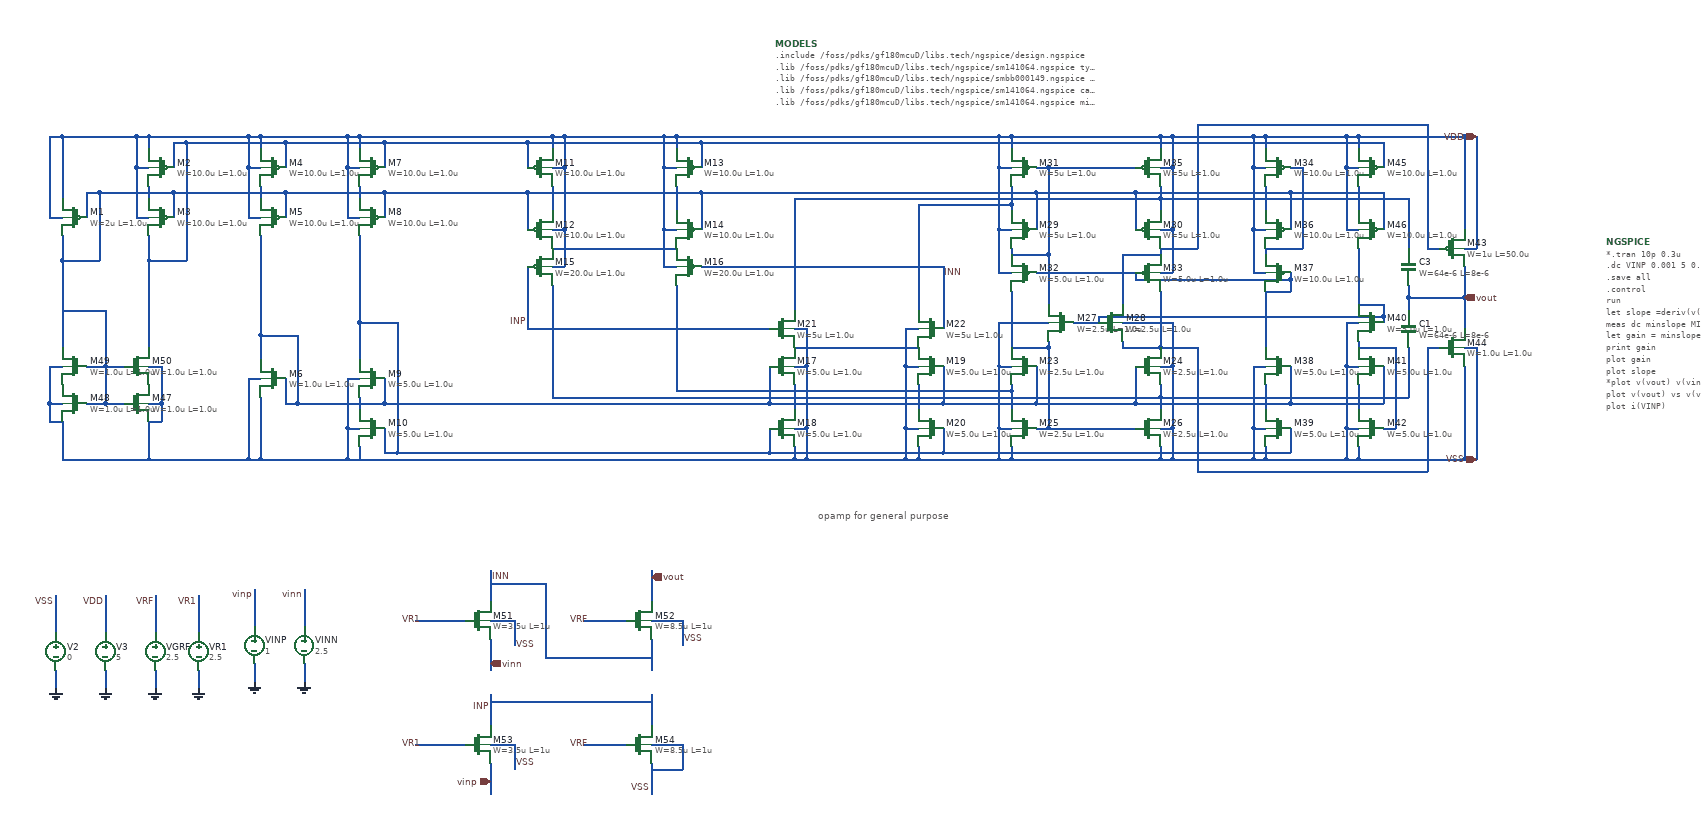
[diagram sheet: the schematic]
v {xschem version=3.4.8RC file_version=1.3}
G {}
K {}
V {}
S {}
F {}
E {}
P 4 1 -1130 460 {}
T {opamp for general purpose} -480 690 2 0 0.4 0.4 {}
N -910 300 -890 300 {
lab=VDD}
N -730 300 -710 300 {
lab=VDD}
N -910 90 -910 110 {
lab=VDD}
N -910 140 -890 140 {
lab=VDD}
N -950 100 -950 140 {
lab=#net1}
N -190 560 -190 610 {
lab=VSS}
N -190 560 -170 560 {
lab=VSS}
N -170 590 -170 610 {
lab=VSS}
N -170 90 -170 110 {
lab=VDD}
N -190 140 -170 140 {
lab=VDD}
N 70 90 70 110 {
lab=VDD}
N 70 140 90 140 {
lab=VDD}
N 90 140 90 240 {
lab=VDD}
N 70 560 90 560 {
lab=VSS}
N 70 590 70 610 {
lab=VSS}
N -950 300 -950 400 {
lab=INP}
N -340 400 -320 400 {
lab=VSS}
N -520 460 -500 460 {
lab=VSS}
N -500 560 -500 610 {
lab=VSS}
N -520 560 -500 560 {
lab=VSS}
N -520 490 -520 530 {
lab=#net2}
N -520 590 -520 610 {
lab=VSS}
N -560 560 -560 600 {
lab=#net3}
N -560 460 -560 520 {
lab=#net4}
N -910 240 -890 240 {
lab=VDD}
N -910 170 -910 210 {
lab=#net5}
N -950 180 -950 240 {
lab=#net6}
N -190 140 -190 240 {
lab=VDD}
N -190 240 -170 240 {
lab=VDD}
N -170 200 -170 210 {
lab=#net7}
N -190 460 -170 460 {
lab=VSS}
N -190 460 -190 560 {
lab=VSS}
N -170 500 -170 530 {
lab=#net8}
N 70 510 70 530 {
lab=#net9}
N 70 460 90 460 {
lab=VSS}
N -670 300 -280 300 {
lab=INN}
N -280 300 -280 400 {
lab=INN}
N 70 240 90 240 {
lab=VDD}
N 70 190 70 210 {
lab=#net10}
N -910 270 -710 270 {
lab=#net11}
N -950 400 -560 400 {
lab=INP}
N -520 430 -320 430 {
lab=#net12}
N -170 270 -170 280 {
lab=#net13}
N -190 310 -170 310 {
lab=VDD}
N -190 240 -190 310 {
lab=VDD}
N -110 560 30 560 {
lab=#net14}
N 90 560 90 610 {
lab=VSS}
N -70 390 -30 390 {
lab=#net15}
N 70 310 90 310 {
lab=VDD}
N 90 240 90 310 {
lab=VDD}
N 70 270 70 280 {
lab=#net16}
N 10 390 90 390 {
lab=VSS}
N 90 390 90 460 {
lab=VSS}
N 560 350 560 400 {
lab=vout}
N 560 270 580 270 {
lab=VDD}
N 580 90 580 270 {
lab=VDD}
N 240 90 370 90 {
lab=VDD}
N 560 430 580 430 {
lab=VSS}
N 580 430 580 610 {
lab=VSS}
N 560 460 560 610 {
lab=VSS}
N 560 90 560 240 {
lab=VDD}
N 220 140 240 140 {
lab=VDD}
N 220 90 220 140 {
lab=VDD}
N 240 90 240 110 {
lab=VDD}
N 240 170 240 210 {
lab=#net17}
N 220 240 240 240 {
lab=VDD}
N 220 140 220 240 {
lab=VDD}
N 240 270 240 280 {
lab=#net18}
N 220 310 240 310 {
lab=VDD}
N 220 240 220 310 {
lab=VDD}
N 220 460 240 460 {
lab=VSS}
N 220 560 220 610 {
lab=VSS}
N 220 560 240 560 {
lab=VSS}
N 240 490 240 530 {
lab=#net19}
N 240 590 240 610 {
lab=VSS}
N 280 560 280 600 {
lab=#net3}
N 280 460 280 520 {
lab=#net4}
N 370 140 390 140 {
lab=VDD}
N 370 90 370 140 {
lab=VDD}
N 390 90 390 110 {
lab=VDD}
N 390 170 390 210 {
lab=#net20}
N 370 240 390 240 {
lab=VDD}
N 370 140 370 240 {
lab=VDD}
N 370 460 390 460 {
lab=VSS}
N 370 560 370 610 {
lab=VSS}
N 370 560 390 560 {
lab=VSS}
N 390 490 390 530 {
lab=#net21}
N 390 590 390 610 {
lab=VSS}
N 390 420 390 430 {
lab=#net22}
N 370 390 390 390 {
lab=VSS}
N 370 390 370 460 {
lab=VSS}
N 390 90 560 90 {
lab=VDD}
N -710 90 -710 110 {
lab=VDD}
N -730 140 -710 140 {
lab=VDD}
N -670 100 -670 140 {
lab=#net1}
N -730 240 -710 240 {
lab=VDD}
N -710 170 -710 210 {
lab=#net23}
N -670 180 -670 240 {
lab=#net6}
N -340 460 -320 460 {
lab=VSS}
N -340 560 -320 560 {
lab=VSS}
N -320 490 -320 530 {
lab=#net24}
N -320 590 -320 610 {
lab=VSS}
N -280 560 -280 600 {
lab=#net3}
N -280 460 -280 520 {
lab=#net4}
N -520 400 -500 400 {
lab=VSS}
N 280 180 280 240 {
lab=#net6}
N 280 140 300 140 {
lab=#net18}
N 300 140 300 270 {
lab=#net18}
N 240 270 300 270 {
lab=#net18}
N 280 320 280 340 {
lab=#net25}
N 240 340 280 340 {
lab=#net25}
N 240 340 240 430 {
lab=#net25}
N 430 100 430 140 {
lab=#net1}
N 430 180 430 240 {
lab=#net6}
N 30 520 280 520 {
lab=#net4}
N 430 460 430 520 {
lab=#net4}
N 430 560 450 560 {
lab=#net22}
N 450 430 450 560 {
lab=#net22}
N 390 430 450 430 {
lab=#net22}
N 430 380 430 390 {
lab=#net15}
N 390 360 430 360 {
lab=#net15}
N 390 270 390 360 {
lab=#net15}
N -110 140 30 140 {
lab=#net13}
N -130 180 -130 240 {
lab=#net6}
N 30 180 30 240 {
lab=#net6}
N -130 310 30 310 {
lab=#net25}
N -170 340 -170 430 {
lab=#net14}
N -110 420 -110 430 {
lab=#net14}
N -170 430 -110 430 {
lab=#net14}
N 10 420 10 430 {
lab=#net26}
N 10 430 70 430 {
lab=#net26}
N -190 390 -110 390 {
lab=VSS}
N -190 390 -190 460 {
lab=VSS}
N 70 340 70 430 {
lab=#net26}
N -110 280 -110 360 {
lab=#net13}
N -170 280 -110 280 {
lab=#net13}
N 10 280 10 360 {
lab=#net16}
N 10 280 70 280 {
lab=#net16}
N 280 180 430 180 {
lab=#net6}
N -280 600 280 600 {
lab=#net3}
N 280 520 430 520 {
lab=#net4}
N 30 320 280 320 {
lab=#net25}
N 30 310 30 320 {
lab=#net25}
N -30 380 430 380 {
lab=#net15}
N -30 380 -30 390 {
lab=#net15}
N -910 330 -910 510 {
lab=#net9}
N -710 330 -710 500 {
lab=#net8}
N -520 190 -520 370 {
lab=#net10}
N -320 200 -320 370 {
lab=#net7}
N -130 460 -130 520 {
lab=#net4}
N 30 460 30 520 {
lab=#net4}
N -110 430 -110 560 {
lab=#net14}
N -110 140 -110 280 {
lab=#net13}
N 560 90 580 90 {
lab=VDD}
N 500 270 520 270 {
lab=#net16}
N 500 70 500 270 {
lab=#net16}
N 130 70 500 70 {
lab=#net16}
N 130 70 130 270 {
lab=#net16}
N 70 270 130 270 {
lab=#net16}
N 500 430 520 430 {
lab=#net26}
N 500 430 500 630 {
lab=#net26}
N 130 630 500 630 {
lab=#net26}
N 130 430 130 630 {
lab=#net26}
N 70 430 130 430 {
lab=#net26}
N 70 510 470 510 {
lab=#net9}
N 470 350 470 370 {
lab=vout}
N -520 190 70 190 {
lab=#net10}
N -320 200 -170 200 {
lab=#net7}
N -710 500 -170 500 {
lab=#net8}
N -910 510 70 510 {
lab=#net9}
N -190 90 -170 90 {
lab=VDD}
N 70 90 90 90 {
lab=VDD}
N 560 610 580 610 {
lab=VSS}
N -560 520 -280 520 {
lab=#net4}
N -560 600 -280 600 {
lab=#net3}
N -950 100 -670 100 {
lab=#net1}
N -950 180 -670 180 {
lab=#net6}
N 30 180 280 180 {
lab=#net6}
N -670 100 430 100 {
lab=#net1}
N -730 90 -710 90 {
lab=VDD}
N -1100 100 -950 100 {
lab=#net1}
N -1100 180 -950 180 {
lab=#net6}
N -1100 520 -560 520 {
lab=#net4}
N -1080 600 -560 600 {
lab=#net3}
N 470 350 560 350 {
lab=vout}
N 470 430 470 510 {
lab=#net9}
N 70 190 470 190 {
lab=#net10}
N 470 190 470 270 {
lab=#net10}
N 470 330 470 350 {
lab=vout}
N -730 140 -730 240 {
lab=VDD}
N -890 140 -890 240 {
lab=VDD}
N -340 560 -340 610 {
lab=VSS}
N -500 400 -500 460 {
lab=VSS}
N -340 400 -340 460 {
lab=VSS}
N -890 240 -890 300 {
lab=VDD}
N -730 240 -730 300 {
lab=VDD}
N -890 90 -890 140 {
lab=VDD}
N -320 610 -190 610 {
lab=VSS}
N -190 610 -170 610 {
lab=VSS}
N -190 90 -190 140 {
lab=VDD}
N -170 90 70 90 {
lab=VDD}
N 90 90 90 140 {
lab=VDD}
N 90 460 90 560 {
lab=VSS}
N -170 610 70 610 {
lab=VSS}
N -520 610 -500 610 {
lab=VSS}
N -500 460 -500 560 {
lab=VSS}
N 70 610 90 610 {
lab=VSS}
N 390 610 560 610 {
lab=VSS}
N 90 90 220 90 {
lab=VDD}
N 220 90 240 90 {
lab=VDD}
N 90 610 220 610 {
lab=VSS}
N 220 460 220 560 {
lab=VSS}
N 220 610 240 610 {
lab=VSS}
N 370 90 390 90 {
lab=VDD}
N 240 610 370 610 {
lab=VSS}
N 370 460 370 560 {
lab=VSS}
N 370 610 390 610 {
lab=VSS}
N -730 90 -730 140 {
lab=VDD}
N -340 460 -340 560 {
lab=VSS}
N -340 610 -320 610 {
lab=VSS}
N -670 180 -130 180 {
lab=#net6}
N -130 180 30 180 {
lab=#net6}
N 280 310 280 320 {
lab=#net25}
N 430 360 430 380 {
lab=#net15}
N -280 520 -130 520 {
lab=#net4}
N -130 520 30 520 {
lab=#net4}
N -130 560 -110 560 {
lab=#net14}
N -130 140 -110 140 {
lab=#net13}
N 70 490 70 510 {
lab=#net9}
N 70 170 70 190 {
lab=#net10}
N -170 170 -170 200 {
lab=#net7}
N -170 490 -170 500 {
lab=#net8}
N 560 300 560 350 {
lab=vout}
N -500 610 -340 610 {
lab=VSS}
N -910 90 -890 90 {
lab=VDD}
N -710 90 -190 90 {
lab=VDD}
N -890 90 -730 90 {
lab=VDD}
N -1240 480 -1220 480 {
lab=VSS}
N -1240 560 -1240 610 {
lab=VSS}
N -1240 560 -1220 560 {
lab=VSS}
N -1220 510 -1220 530 {
lab=#net27}
N -1220 590 -1220 610 {
lab=VSS}
N -1220 90 -1220 110 {
lab=VDD}
N -1240 140 -1220 140 {
lab=VDD}
N -1240 220 -1220 220 {
lab=VDD}
N -1240 140 -1240 220 {
lab=VDD}
N -1220 170 -1220 190 {
lab=#net28}
N -1180 180 -1180 220 {
lab=#net6}
N -1180 100 -1180 140 {
lab=#net1}
N -1380 90 -1380 110 {
lab=VDD}
N -1400 140 -1380 140 {
lab=VDD}
N -1400 220 -1380 220 {
lab=VDD}
N -1400 140 -1400 220 {
lab=VDD}
N -1380 170 -1380 190 {
lab=#net29}
N -1340 180 -1340 220 {
lab=#net6}
N -1340 100 -1340 140 {
lab=#net1}
N -1400 480 -1380 480 {
lab=VSS}
N -1400 480 -1400 610 {
lab=VSS}
N -1380 510 -1380 610 {
lab=VSS}
N -1340 480 -1340 520 {
lab=#net4}
N -1340 520 -1320 520 {
lab=#net4}
N -1380 410 -1320 410 {
lab=#net4}
N -1180 480 -1180 520 {
lab=#net4}
N -1180 560 -1180 600 {
lab=#net3}
N -1180 600 -1160 600 {
lab=#net3}
N -1320 520 -1180 520 {
lab=#net4}
N -1220 390 -1160 390 {
lab=#net3}
N -1380 250 -1380 410 {
lab=#net4}
N -1220 250 -1220 390 {
lab=#net3}
N -1320 410 -1320 520 {
lab=#net4}
N -1160 390 -1160 600 {
lab=#net3}
N -1220 390 -1220 450 {
lab=#net3}
N -1380 410 -1380 450 {
lab=#net4}
N -1180 100 -1030 100 {
lab=#net1}
N -1180 180 -1030 180 {
lab=#net6}
N -1560 610 -1400 610 {
lab=VSS}
N -1560 90 -1560 110 {
lab=VDD}
N -1580 140 -1560 140 {
lab=VDD}
N -1580 220 -1560 220 {
lab=VDD}
N -1580 140 -1580 220 {
lab=VDD}
N -1560 170 -1560 190 {
lab=#net30}
N -1520 180 -1520 220 {
lab=#net6}
N -1520 100 -1520 140 {
lab=#net1}
N -1560 290 -1500 290 {
lab=#net1}
N -1560 290 -1560 430 {
lab=#net1}
N -1700 90 -1700 190 {
lab=VDD}
N -1720 220 -1700 220 {
lab=VDD}
N -1720 90 -1720 220 {
lab=VDD}
N -1640 180 -1520 180 {
lab=#net6}
N -1660 180 -1660 220 {
lab=#net6}
N -1700 290 -1640 290 {
lab=#net6}
N -1700 290 -1700 430 {
lab=#net6}
N -1700 250 -1700 290 {
lab=#net6}
N -1560 250 -1560 290 {
lab=#net1}
N -1640 180 -1640 290 {
lab=#net6}
N -1500 100 -1500 290 {
lab=#net1}
N -1700 550 -1700 610 {
lab=VSS}
N -1560 550 -1560 610 {
lab=VSS}
N -1630 520 -1600 520 {
lab=#net6}
N -1720 520 -1700 520 {
lab=VSS}
N -1720 520 -1720 550 {
lab=VSS}
N -1720 550 -1700 550 {
lab=VSS}
N -1560 520 -1540 520 {
lab=VSS}
N -1540 520 -1540 550 {
lab=VSS}
N -1560 550 -1540 550 {
lab=VSS}
N -1630 460 -1600 460 {
lab=#net6}
N -1630 460 -1630 520 {
lab=#net6}
N -1720 460 -1700 460 {
lab=VSS}
N -1720 460 -1720 520 {
lab=VSS}
N -1560 460 -1540 460 {
lab=VSS}
N -1540 460 -1540 520 {
lab=VSS}
N -1630 440 -1630 460 {
lab=#net6}
N -1380 610 -1240 610 {
lab=VSS}
N -1240 480 -1240 560 {
lab=VSS}
N -1240 610 -1220 610 {
lab=VSS}
N -1240 90 -1220 90 {
lab=VDD}
N -1240 90 -1240 140 {
lab=VDD}
N -1340 180 -1180 180 {
lab=#net6}
N -1340 100 -1180 100 {
lab=#net1}
N -1400 90 -1380 90 {
lab=VDD}
N -1400 90 -1400 140 {
lab=VDD}
N -1520 180 -1340 180 {
lab=#net6}
N -1500 100 -1340 100 {
lab=#net1}
N -1400 610 -1380 610 {
lab=VSS}
N -1580 90 -1560 90 {
lab=VDD}
N -1580 90 -1580 140 {
lab=VDD}
N -1720 90 -1700 90 {
lab=VDD}
N -1660 180 -1640 180 {
lab=#net6}
N -1520 100 -1500 100 {
lab=#net1}
N -1700 610 -1560 610 {
lab=VSS}
N -1660 460 -1630 460 {
lab=#net6}
N -1660 520 -1630 520 {
lab=#net6}
N -1380 90 -1240 90 {
lab=VDD}
N -1560 90 -1400 90 {
lab=VDD}
N -1700 90 -1580 90 {
lab=VDD}
N -1700 370 -1630 370 {lab=#net6}
N -1630 370 -1630 440 {lab=#net6}
N -1180 520 -1040 520 {lab=#net4}
N -1160 600 -1040 600 {lab=#net3}
N -1220 90 -910 90 {lab=VDD}
N -1230 610 -520 610 {lab=VSS}
N -1710 950 -1710 980 {lab=0}
N -1710 830 -1710 890 {lab=VSS}
N -1630 950 -1630 980 {lab=0}
N -1630 830 -1630 890 {lab=VDD}
N -1550 950 -1550 980 {lab=0}
N -1550 830 -1550 890 {lab=VRF}
N -1390 940 -1390 970 {lab=0}
N -1390 820 -1390 880 {lab=vinp}
N -1310 940 -1310 970 {lab=0}
N -1310 820 -1310 880 {lab=vinn}
N -1480 950 -1480 980 {lab=0}
N -1480 830 -1480 890 {lab=VR1}
N -1010 900 -1010 950 {lab=vinn}
N -1010 870 -970 870 {lab=VSS}
N -970 870 -970 910 {lab=VSS}
N -1130 870 -1050 870 {lab=VR1}
N -1010 790 -1010 840 {lab=INN}
N -1010 1100 -1010 1150 {lab=vinp}
N -1010 1070 -970 1070 {lab=VSS}
N -970 1070 -970 1110 {lab=VSS}
N -1130 1070 -1050 1070 {lab=VR1}
N -1010 990 -1010 1040 {lab=INP}
N -750 900 -750 950 {lab=INN}
N -750 870 -700 870 {lab=VSS}
N -700 870 -700 910 {lab=VSS}
N -860 870 -790 870 {lab=VRF}
N -750 790 -750 840 {lab=vout}
N -750 1100 -750 1150 {lab=VSS}
N -750 1070 -700 1070 {lab=VSS}
N -700 1070 -700 1110 {lab=VSS}
N -750 1110 -700 1110 {lab=VSS}
N -860 1070 -790 1070 {lab=VRF}
N -750 990 -750 1040 {lab=INP}
N -1010 810 -920 810 {lab=INN}
N -920 810 -920 930 {lab=INN}
N -920 930 -750 930 {lab=INN}
N -1010 1000 -750 1000 {lab=INP}
C {devices/opin.sym} 560 350 0 0 {name=p1 lab=vout}
C {devices/iopin.sym} 580 90 0 0 {name=p3 lab=VDD}
C {devices/iopin.sym} 580 610 0 0 {name=p4 lab=VSS}
C {devices/ipin.sym} -1010 1130 0 0 {name=p2 lab=vinp}
C {devices/ipin.sym} -1010 940 0 1 {name=p5 lab=vinn}
C {symbols/pfet_06v0.sym} -930 140 0 0 {name=M11
L=1.0u
W=10.0u
nf=1
m=1
ad="'int((nf+1)/2) * W/nf * 0.18u'"
pd="'2*int((nf+1)/2) * (W/nf + 0.18u)'"
as="'int((nf+2)/2) * W/nf * 0.18u'"
ps="'2*int((nf+2)/2) * (W/nf + 0.18u)'"
nrd="'0.18u / W'" nrs="'0.18u / W'"
sa=0 sb=0 sd=0
model=pfet_06v0
spiceprefix=X
}
C {symbols/pfet_06v0.sym} -930 240 0 0 {name=M12
L=1.0u
W=10.0u
nf=1
m=1
ad="'int((nf+1)/2) * W/nf * 0.18u'"
pd="'2*int((nf+1)/2) * (W/nf + 0.18u)'"
as="'int((nf+2)/2) * W/nf * 0.18u'"
ps="'2*int((nf+2)/2) * (W/nf + 0.18u)'"
nrd="'0.18u / W'" nrs="'0.18u / W'"
sa=0 sb=0 sd=0
model=pfet_06v0
spiceprefix=X
}
C {symbols/pfet_06v0.sym} -690 140 0 1 {name=M13
L=1.0u
W=10.0u
nf=1
m=1
ad="'int((nf+1)/2) * W/nf * 0.18u'"
pd="'2*int((nf+1)/2) * (W/nf + 0.18u)'"
as="'int((nf+2)/2) * W/nf * 0.18u'"
ps="'2*int((nf+2)/2) * (W/nf + 0.18u)'"
nrd="'0.18u / W'" nrs="'0.18u / W'"
sa=0 sb=0 sd=0
model=pfet_06v0
spiceprefix=X
}
C {symbols/pfet_06v0.sym} -690 240 0 1 {name=M14
L=1.0u
W=10.0u
nf=1
m=1
ad="'int((nf+1)/2) * W/nf * 0.18u'"
pd="'2*int((nf+1)/2) * (W/nf + 0.18u)'"
as="'int((nf+2)/2) * W/nf * 0.18u'"
ps="'2*int((nf+2)/2) * (W/nf + 0.18u)'"
nrd="'0.18u / W'" nrs="'0.18u / W'"
sa=0 sb=0 sd=0
model=pfet_06v0
spiceprefix=X
}
C {symbols/pfet_06v0.sym} -930 300 0 0 {name=M15
L=1.0u
W=20.0u
nf=2
m=1
ad="'int((nf+1)/2) * W/nf * 0.18u'"
pd="'2*int((nf+1)/2) * (W/nf + 0.18u)'"
as="'int((nf+2)/2) * W/nf * 0.18u'"
ps="'2*int((nf+2)/2) * (W/nf + 0.18u)'"
nrd="'0.18u / W'" nrs="'0.18u / W'"
sa=0 sb=0 sd=0
model=pfet_06v0
spiceprefix=X
}
C {symbols/pfet_06v0.sym} -690 300 0 1 {name=M16
L=1.0u
W=20.0u
nf=2
m=1
ad="'int((nf+1)/2) * W/nf * 0.18u'"
pd="'2*int((nf+1)/2) * (W/nf + 0.18u)'"
as="'int((nf+2)/2) * W/nf * 0.18u'"
ps="'2*int((nf+2)/2) * (W/nf + 0.18u)'"
nrd="'0.18u / W'" nrs="'0.18u / W'"
sa=0 sb=0 sd=0
model=pfet_06v0
spiceprefix=X
}
C {symbols/nfet_06v0.sym} -540 460 0 0 {name=M17
L=1.0u
W=5.0u
nf=1
m=1
ad="'int((nf+1)/2) * W/nf * 0.18u'"
pd="'2*int((nf+1)/2) * (W/nf + 0.18u)'"
as="'int((nf+2)/2) * W/nf * 0.18u'"
ps="'2*int((nf+2)/2) * (W/nf + 0.18u)'"
nrd="'0.18u / W'" nrs="'0.18u / W'"
sa=0 sb=0 sd=0
model=nfet_06v0
spiceprefix=X
}
C {symbols/nfet_06v0.sym} -540 560 0 0 {name=M18
L=1.0u
W=5.0u
nf=1
m=1
ad="'int((nf+1)/2) * W/nf * 0.18u'"
pd="'2*int((nf+1)/2) * (W/nf + 0.18u)'"
as="'int((nf+2)/2) * W/nf * 0.18u'"
ps="'2*int((nf+2)/2) * (W/nf + 0.18u)'"
nrd="'0.18u / W'" nrs="'0.18u / W'"
sa=0 sb=0 sd=0
model=nfet_06v0
spiceprefix=X
}
C {symbols/nfet_06v0.sym} -300 460 0 1 {name=M19
L=1.0u
W=5.0u
nf=1
m=1
ad="'int((nf+1)/2) * W/nf * 0.18u'"
pd="'2*int((nf+1)/2) * (W/nf + 0.18u)'"
as="'int((nf+2)/2) * W/nf * 0.18u'"
ps="'2*int((nf+2)/2) * (W/nf + 0.18u)'"
nrd="'0.18u / W'" nrs="'0.18u / W'"
sa=0 sb=0 sd=0
model=nfet_06v0
spiceprefix=X
}
C {symbols/nfet_06v0.sym} -300 560 0 1 {name=M20
L=1.0u
W=5.0u
nf=1
m=1
ad="'int((nf+1)/2) * W/nf * 0.18u'"
pd="'2*int((nf+1)/2) * (W/nf + 0.18u)'"
as="'int((nf+2)/2) * W/nf * 0.18u'"
ps="'2*int((nf+2)/2) * (W/nf + 0.18u)'"
nrd="'0.18u / W'" nrs="'0.18u / W'"
sa=0 sb=0 sd=0
model=nfet_06v0
spiceprefix=X
}
C {symbols/nfet_06v0.sym} -540 400 0 0 {name=M21
L=1.0u
W=5u
nf=2
m=1
ad="'int((nf+1)/2) * W/nf * 0.18u'"
pd="'2*int((nf+1)/2) * (W/nf + 0.18u)'"
as="'int((nf+2)/2) * W/nf * 0.18u'"
ps="'2*int((nf+2)/2) * (W/nf + 0.18u)'"
nrd="'0.18u / W'" nrs="'0.18u / W'"
sa=0 sb=0 sd=0
model=nfet_06v0
spiceprefix=X
}
C {symbols/nfet_06v0.sym} -300 400 0 1 {name=M22
L=1.0u
W=5u
nf=2
m=1
ad="'int((nf+1)/2) * W/nf * 0.18u'"
pd="'2*int((nf+1)/2) * (W/nf + 0.18u)'"
as="'int((nf+2)/2) * W/nf * 0.18u'"
ps="'2*int((nf+2)/2) * (W/nf + 0.18u)'"
nrd="'0.18u / W'" nrs="'0.18u / W'"
sa=0 sb=0 sd=0
model=nfet_06v0
spiceprefix=X
}
C {symbols/pfet_06v0.sym} -150 240 0 1 {name=M29
L=1.0u
W=5u
nf=2
m=1
ad="'int((nf+1)/2) * W/nf * 0.18u'"
pd="'2*int((nf+1)/2) * (W/nf + 0.18u)'"
as="'int((nf+2)/2) * W/nf * 0.18u'"
ps="'2*int((nf+2)/2) * (W/nf + 0.18u)'"
nrd="'0.18u / W'" nrs="'0.18u / W'"
sa=0 sb=0 sd=0
model=pfet_06v0
spiceprefix=X
}
C {symbols/pfet_06v0.sym} 50 240 0 0 {name=M30
L=1.0u
W=5u
nf=2
m=1
ad="'int((nf+1)/2) * W/nf * 0.18u'"
pd="'2*int((nf+1)/2) * (W/nf + 0.18u)'"
as="'int((nf+2)/2) * W/nf * 0.18u'"
ps="'2*int((nf+2)/2) * (W/nf + 0.18u)'"
nrd="'0.18u / W'" nrs="'0.18u / W'"
sa=0 sb=0 sd=0
model=pfet_06v0
spiceprefix=X
}
C {symbols/pfet_06v0.sym} -150 140 0 1 {name=M31
L=1.0u
W=5u
nf=4
m=1
ad="'int((nf+1)/2) * W/nf * 0.18u'"
pd="'2*int((nf+1)/2) * (W/nf + 0.18u)'"
as="'int((nf+2)/2) * W/nf * 0.18u'"
ps="'2*int((nf+2)/2) * (W/nf + 0.18u)'"
nrd="'0.18u / W'" nrs="'0.18u / W'"
sa=0 sb=0 sd=0
model=pfet_06v0
spiceprefix=X
}
C {symbols/pfet_06v0.sym} 50 140 0 0 {name=M35
L=1.0u
W=5u
nf=4
m=1
ad="'int((nf+1)/2) * W/nf * 0.18u'"
pd="'2*int((nf+1)/2) * (W/nf + 0.18u)'"
as="'int((nf+2)/2) * W/nf * 0.18u'"
ps="'2*int((nf+2)/2) * (W/nf + 0.18u)'"
nrd="'0.18u / W'" nrs="'0.18u / W'"
sa=0 sb=0 sd=0
model=pfet_06v0
spiceprefix=X
}
C {symbols/pfet_06v0.sym} -150 310 0 1 {name=M32
L=1.0u
W=5.0u
nf=2
m=1
ad="'int((nf+1)/2) * W/nf * 0.18u'"
pd="'2*int((nf+1)/2) * (W/nf + 0.18u)'"
as="'int((nf+2)/2) * W/nf * 0.18u'"
ps="'2*int((nf+2)/2) * (W/nf + 0.18u)'"
nrd="'0.18u / W'" nrs="'0.18u / W'"
sa=0 sb=0 sd=0
model=pfet_06v0
spiceprefix=X
}
C {symbols/pfet_06v0.sym} 50 310 0 0 {name=M33
L=1.0u
W=5.0u
nf=2
m=1
ad="'int((nf+1)/2) * W/nf * 0.18u'"
pd="'2*int((nf+1)/2) * (W/nf + 0.18u)'"
as="'int((nf+2)/2) * W/nf * 0.18u'"
ps="'2*int((nf+2)/2) * (W/nf + 0.18u)'"
nrd="'0.18u / W'" nrs="'0.18u / W'"
sa=0 sb=0 sd=0
model=pfet_06v0
spiceprefix=X
}
C {symbols/nfet_06v0.sym} -150 460 0 1 {name=M23
L=1.0u
W=2.5u
nf=2
m=1
ad="'int((nf+1)/2) * W/nf * 0.18u'"
pd="'2*int((nf+1)/2) * (W/nf + 0.18u)'"
as="'int((nf+2)/2) * W/nf * 0.18u'"
ps="'2*int((nf+2)/2) * (W/nf + 0.18u)'"
nrd="'0.18u / W'" nrs="'0.18u / W'"
sa=0 sb=0 sd=0
model=nfet_06v0
spiceprefix=X
}
C {symbols/nfet_06v0.sym} 50 460 0 0 {name=M24
L=1.0u
W=2.5u
nf=2
m=1
ad="'int((nf+1)/2) * W/nf * 0.18u'"
pd="'2*int((nf+1)/2) * (W/nf + 0.18u)'"
as="'int((nf+2)/2) * W/nf * 0.18u'"
ps="'2*int((nf+2)/2) * (W/nf + 0.18u)'"
nrd="'0.18u / W'" nrs="'0.18u / W'"
sa=0 sb=0 sd=0
model=nfet_06v0
spiceprefix=X
}
C {symbols/nfet_06v0.sym} -150 560 0 1 {name=M25
L=1.0u
W=2.5u
nf=4
m=1
ad="'int((nf+1)/2) * W/nf * 0.18u'"
pd="'2*int((nf+1)/2) * (W/nf + 0.18u)'"
as="'int((nf+2)/2) * W/nf * 0.18u'"
ps="'2*int((nf+2)/2) * (W/nf + 0.18u)'"
nrd="'0.18u / W'" nrs="'0.18u / W'"
sa=0 sb=0 sd=0
model=nfet_06v0
spiceprefix=X
}
C {symbols/nfet_06v0.sym} 50 560 0 0 {name=M26
L=1.0u
W=2.5u
nf=4
m=1
ad="'int((nf+1)/2) * W/nf * 0.18u'"
pd="'2*int((nf+1)/2) * (W/nf + 0.18u)'"
as="'int((nf+2)/2) * W/nf * 0.18u'"
ps="'2*int((nf+2)/2) * (W/nf + 0.18u)'"
nrd="'0.18u / W'" nrs="'0.18u / W'"
sa=0 sb=0 sd=0
model=nfet_06v0
spiceprefix=X
}
C {symbols/nfet_06v0.sym} -90 390 0 1 {name=M27
L=1.0u
W=2.5u
nf=1
m=1
ad="'int((nf+1)/2) * W/nf * 0.18u'"
pd="'2*int((nf+1)/2) * (W/nf + 0.18u)'"
as="'int((nf+2)/2) * W/nf * 0.18u'"
ps="'2*int((nf+2)/2) * (W/nf + 0.18u)'"
nrd="'0.18u / W'" nrs="'0.18u / W'"
sa=0 sb=0 sd=0
model=nfet_06v0
spiceprefix=X
}
C {symbols/nfet_06v0.sym} -10 390 0 0 {name=M28
L=1.0u
W=2.5u
nf=1
m=1
ad="'int((nf+1)/2) * W/nf * 0.18u'"
pd="'2*int((nf+1)/2) * (W/nf + 0.18u)'"
as="'int((nf+2)/2) * W/nf * 0.18u'"
ps="'2*int((nf+2)/2) * (W/nf + 0.18u)'"
nrd="'0.18u / W'" nrs="'0.18u / W'"
sa=0 sb=0 sd=0
model=nfet_06v0
spiceprefix=X
}
C {symbols/pfet_06v0.sym} 260 140 0 1 {name=M34
L=1.0u
W=10.0u
nf=1
m=1
ad="'int((nf+1)/2) * W/nf * 0.18u'"
pd="'2*int((nf+1)/2) * (W/nf + 0.18u)'"
as="'int((nf+2)/2) * W/nf * 0.18u'"
ps="'2*int((nf+2)/2) * (W/nf + 0.18u)'"
nrd="'0.18u / W'" nrs="'0.18u / W'"
sa=0 sb=0 sd=0
model=pfet_06v0
spiceprefix=X
}
C {symbols/pfet_06v0.sym} 260 240 0 1 {name=M36
L=1.0u
W=10.0u
nf=1
m=1
ad="'int((nf+1)/2) * W/nf * 0.18u'"
pd="'2*int((nf+1)/2) * (W/nf + 0.18u)'"
as="'int((nf+2)/2) * W/nf * 0.18u'"
ps="'2*int((nf+2)/2) * (W/nf + 0.18u)'"
nrd="'0.18u / W'" nrs="'0.18u / W'"
sa=0 sb=0 sd=0
model=pfet_06v0
spiceprefix=X
}
C {symbols/pfet_06v0.sym} 260 310 0 1 {name=M37
L=1.0u
W=10.0u
nf=1
m=1
ad="'int((nf+1)/2) * W/nf * 0.18u'"
pd="'2*int((nf+1)/2) * (W/nf + 0.18u)'"
as="'int((nf+2)/2) * W/nf * 0.18u'"
ps="'2*int((nf+2)/2) * (W/nf + 0.18u)'"
nrd="'0.18u / W'" nrs="'0.18u / W'"
sa=0 sb=0 sd=0
model=pfet_06v0
spiceprefix=X
}
C {symbols/nfet_06v0.sym} 260 460 0 1 {name=M38
L=1.0u
W=5.0u
nf=1
m=1
ad="'int((nf+1)/2) * W/nf * 0.18u'"
pd="'2*int((nf+1)/2) * (W/nf + 0.18u)'"
as="'int((nf+2)/2) * W/nf * 0.18u'"
ps="'2*int((nf+2)/2) * (W/nf + 0.18u)'"
nrd="'0.18u / W'" nrs="'0.18u / W'"
sa=0 sb=0 sd=0
model=nfet_06v0
spiceprefix=X
}
C {symbols/nfet_06v0.sym} 260 560 0 1 {name=M39
L=1.0u
W=5.0u
nf=1
m=1
ad="'int((nf+1)/2) * W/nf * 0.18u'"
pd="'2*int((nf+1)/2) * (W/nf + 0.18u)'"
as="'int((nf+2)/2) * W/nf * 0.18u'"
ps="'2*int((nf+2)/2) * (W/nf + 0.18u)'"
nrd="'0.18u / W'" nrs="'0.18u / W'"
sa=0 sb=0 sd=0
model=nfet_06v0
spiceprefix=X
}
C {symbols/pfet_06v0.sym} 410 140 0 1 {name=M45
L=1.0u
W=10.0u
nf=1
m=1
ad="'int((nf+1)/2) * W/nf * 0.18u'"
pd="'2*int((nf+1)/2) * (W/nf + 0.18u)'"
as="'int((nf+2)/2) * W/nf * 0.18u'"
ps="'2*int((nf+2)/2) * (W/nf + 0.18u)'"
nrd="'0.18u / W'" nrs="'0.18u / W'"
sa=0 sb=0 sd=0
model=pfet_06v0
spiceprefix=X
}
C {symbols/pfet_06v0.sym} 410 240 0 1 {name=M46
L=1.0u
W=10.0u
nf=1
m=1
ad="'int((nf+1)/2) * W/nf * 0.18u'"
pd="'2*int((nf+1)/2) * (W/nf + 0.18u)'"
as="'int((nf+2)/2) * W/nf * 0.18u'"
ps="'2*int((nf+2)/2) * (W/nf + 0.18u)'"
nrd="'0.18u / W'" nrs="'0.18u / W'"
sa=0 sb=0 sd=0
model=pfet_06v0
spiceprefix=X
}
C {symbols/nfet_06v0.sym} 410 390 0 1 {name=M40
L=1.0u
W=5.0u
nf=1
m=1
ad="'int((nf+1)/2) * W/nf * 0.18u'"
pd="'2*int((nf+1)/2) * (W/nf + 0.18u)'"
as="'int((nf+2)/2) * W/nf * 0.18u'"
ps="'2*int((nf+2)/2) * (W/nf + 0.18u)'"
nrd="'0.18u / W'" nrs="'0.18u / W'"
sa=0 sb=0 sd=0
model=nfet_06v0
spiceprefix=X
}
C {symbols/nfet_06v0.sym} 410 460 0 1 {name=M41
L=1.0u
W=5.0u
nf=1
m=1
ad="'int((nf+1)/2) * W/nf * 0.18u'"
pd="'2*int((nf+1)/2) * (W/nf + 0.18u)'"
as="'int((nf+2)/2) * W/nf * 0.18u'"
ps="'2*int((nf+2)/2) * (W/nf + 0.18u)'"
nrd="'0.18u / W'" nrs="'0.18u / W'"
sa=0 sb=0 sd=0
model=nfet_06v0
spiceprefix=X
}
C {symbols/nfet_06v0.sym} 410 560 0 1 {name=M42
L=1.0u
W=5.0u
nf=1
m=1
ad="'int((nf+1)/2) * W/nf * 0.18u'"
pd="'2*int((nf+1)/2) * (W/nf + 0.18u)'"
as="'int((nf+2)/2) * W/nf * 0.18u'"
ps="'2*int((nf+2)/2) * (W/nf + 0.18u)'"
nrd="'0.18u / W'" nrs="'0.18u / W'"
sa=0 sb=0 sd=0
model=nfet_06v0
spiceprefix=X
}
C {symbols/pfet_06v0.sym} 540 270 0 0 {name=M43
L=50.0u
W=1u
nf=1
m=1
ad="'int((nf+1)/2) * W/nf * 0.18u'"
pd="'2*int((nf+1)/2) * (W/nf + 0.18u)'"
as="'int((nf+2)/2) * W/nf * 0.18u'"
ps="'2*int((nf+2)/2) * (W/nf + 0.18u)'"
nrd="'0.18u / W'" nrs="'0.18u / W'"
sa=0 sb=0 sd=0
model=pfet_06v0
spiceprefix=X
}
C {symbols/nfet_06v0.sym} 540 430 0 0 {name=M44
L=1.0u
W=1.0u
nf=14
m=1
ad="'int((nf+1)/2) * W/nf * 0.18u'"
pd="'2*int((nf+1)/2) * (W/nf + 0.18u)'"
as="'int((nf+2)/2) * W/nf * 0.18u'"
ps="'2*int((nf+2)/2) * (W/nf + 0.18u)'"
nrd="'0.18u / W'" nrs="'0.18u / W'"
sa=0 sb=0 sd=0
model=nfet_06v0
spiceprefix=X
}
C {symbols/cap_mim_2f0fF.sym} 470 300 0 0 {name=C3
W=64e-6
L=8e-6
model=cap_mim_2f0fF
spiceprefix=X
m=1}
C {symbols/cap_mim_2f0fF.sym} 470 400 0 0 {name=C1
W=64e-6
L=8e-6
model=cap_mim_2f0fF
spiceprefix=X
m=1}
C {symbols/pfet_06v0.sym} -1360 140 0 1 {name=M4
L=1.0u
W=10.0u
nf=1
m=1
ad="'int((nf+1)/2) * W/nf * 0.18u'"
pd="'2*int((nf+1)/2) * (W/nf + 0.18u)'"
as="'int((nf+2)/2) * W/nf * 0.18u'"
ps="'2*int((nf+2)/2) * (W/nf + 0.18u)'"
nrd="'0.18u / W'" nrs="'0.18u / W'"
sa=0 sb=0 sd=0
model=pfet_06v0
spiceprefix=X
}
C {symbols/pfet_06v0.sym} -1360 220 0 1 {name=M5
L=1.0u
W=10.0u
nf=1
m=1
ad="'int((nf+1)/2) * W/nf * 0.18u'"
pd="'2*int((nf+1)/2) * (W/nf + 0.18u)'"
as="'int((nf+2)/2) * W/nf * 0.18u'"
ps="'2*int((nf+2)/2) * (W/nf + 0.18u)'"
nrd="'0.18u / W'" nrs="'0.18u / W'"
sa=0 sb=0 sd=0
model=pfet_06v0
spiceprefix=X
}
C {symbols/nfet_06v0.sym} -1360 480 0 1 {name=M6
L=1.0u
W=1.0u
nf=1
m=1
ad="'int((nf+1)/2) * W/nf * 0.18u'"
pd="'2*int((nf+1)/2) * (W/nf + 0.18u)'"
as="'int((nf+2)/2) * W/nf * 0.18u'"
ps="'2*int((nf+2)/2) * (W/nf + 0.18u)'"
nrd="'0.18u / W'" nrs="'0.18u / W'"
sa=0 sb=0 sd=0
model=nfet_06v0
spiceprefix=X
}
C {symbols/pfet_06v0.sym} -1200 140 0 1 {name=M7
L=1.0u
W=10.0u
nf=1
m=1
ad="'int((nf+1)/2) * W/nf * 0.18u'"
pd="'2*int((nf+1)/2) * (W/nf + 0.18u)'"
as="'int((nf+2)/2) * W/nf * 0.18u'"
ps="'2*int((nf+2)/2) * (W/nf + 0.18u)'"
nrd="'0.18u / W'" nrs="'0.18u / W'"
sa=0 sb=0 sd=0
model=pfet_06v0
spiceprefix=X
}
C {symbols/pfet_06v0.sym} -1200 220 0 1 {name=M8
L=1.0u
W=10.0u
nf=1
m=1
ad="'int((nf+1)/2) * W/nf * 0.18u'"
pd="'2*int((nf+1)/2) * (W/nf + 0.18u)'"
as="'int((nf+2)/2) * W/nf * 0.18u'"
ps="'2*int((nf+2)/2) * (W/nf + 0.18u)'"
nrd="'0.18u / W'" nrs="'0.18u / W'"
sa=0 sb=0 sd=0
model=pfet_06v0
spiceprefix=X
}
C {symbols/nfet_06v0.sym} -1200 480 0 1 {name=M9
L=1.0u
W=5.0u
nf=1
m=1
ad="'int((nf+1)/2) * W/nf * 0.18u'"
pd="'2*int((nf+1)/2) * (W/nf + 0.18u)'"
as="'int((nf+2)/2) * W/nf * 0.18u'"
ps="'2*int((nf+2)/2) * (W/nf + 0.18u)'"
nrd="'0.18u / W'" nrs="'0.18u / W'"
sa=0 sb=0 sd=0
model=nfet_06v0
spiceprefix=X
}
C {symbols/nfet_06v0.sym} -1200 560 0 1 {name=M10
L=1.0u
W=5.0u
nf=1
m=1
ad="'int((nf+1)/2) * W/nf * 0.18u'"
pd="'2*int((nf+1)/2) * (W/nf + 0.18u)'"
as="'int((nf+2)/2) * W/nf * 0.18u'"
ps="'2*int((nf+2)/2) * (W/nf + 0.18u)'"
nrd="'0.18u / W'" nrs="'0.18u / W'"
sa=0 sb=0 sd=0
model=nfet_06v0
spiceprefix=X
}
C {symbols/pfet_06v0.sym} -1680 220 0 1 {name=M1
L=1.0u
W=2u
nf=1
m=1
ad="'int((nf+1)/2) * W/nf * 0.18u'"
pd="'2*int((nf+1)/2) * (W/nf + 0.18u)'"
as="'int((nf+2)/2) * W/nf * 0.18u'"
ps="'2*int((nf+2)/2) * (W/nf + 0.18u)'"
nrd="'0.18u / W'" nrs="'0.18u / W'"
sa=0 sb=0 sd=0
model=pfet_06v0
spiceprefix=X
}
C {symbols/pfet_06v0.sym} -1540 140 0 1 {name=M2
L=1.0u
W=10.0u
nf=1
m=1
ad="'int((nf+1)/2) * W/nf * 0.18u'"
pd="'2*int((nf+1)/2) * (W/nf + 0.18u)'"
as="'int((nf+2)/2) * W/nf * 0.18u'"
ps="'2*int((nf+2)/2) * (W/nf + 0.18u)'"
nrd="'0.18u / W'" nrs="'0.18u / W'"
sa=0 sb=0 sd=0
model=pfet_06v0
spiceprefix=X
}
C {symbols/pfet_06v0.sym} -1540 220 0 1 {name=M3
L=1.0u
W=10.0u
nf=1
m=1
ad="'int((nf+1)/2) * W/nf * 0.18u'"
pd="'2*int((nf+1)/2) * (W/nf + 0.18u)'"
as="'int((nf+2)/2) * W/nf * 0.18u'"
ps="'2*int((nf+2)/2) * (W/nf + 0.18u)'"
nrd="'0.18u / W'" nrs="'0.18u / W'"
sa=0 sb=0 sd=0
model=pfet_06v0
spiceprefix=X
}
C {symbols/nfet_06v0.sym} -1580 520 0 0 {name=M47
L=1.0u
W=1.0u
nf=1
m=1
ad="'int((nf+1)/2) * W/nf * 0.18u'"
pd="'2*int((nf+1)/2) * (W/nf + 0.18u)'"
as="'int((nf+2)/2) * W/nf * 0.18u'"
ps="'2*int((nf+2)/2) * (W/nf + 0.18u)'"
nrd="'0.18u / W'" nrs="'0.18u / W'"
sa=0 sb=0 sd=0
model=nfet_06v0
spiceprefix=X
}
C {symbols/nfet_06v0.sym} -1680 520 0 1 {name=M48
L=1.0u
W=1.0u
nf=1
m=1
ad="'int((nf+1)/2) * W/nf * 0.18u'"
pd="'2*int((nf+1)/2) * (W/nf + 0.18u)'"
as="'int((nf+2)/2) * W/nf * 0.18u'"
ps="'2*int((nf+2)/2) * (W/nf + 0.18u)'"
nrd="'0.18u / W'" nrs="'0.18u / W'"
sa=0 sb=0 sd=0
model=nfet_06v0
spiceprefix=X
}
C {symbols/nfet_06v0.sym} -1680 460 0 1 {name=M49
L=1.0u
W=1.0u
nf=1
m=1
ad="'int((nf+1)/2) * W/nf * 0.18u'"
pd="'2*int((nf+1)/2) * (W/nf + 0.18u)'"
as="'int((nf+2)/2) * W/nf * 0.18u'"
ps="'2*int((nf+2)/2) * (W/nf + 0.18u)'"
nrd="'0.18u / W'" nrs="'0.18u / W'"
sa=0 sb=0 sd=0
model=nfet_06v0
spiceprefix=X
}
C {symbols/nfet_06v0.sym} -1580 460 0 0 {name=M50
L=1.0u
W=1.0u
nf=1
m=1
ad="'int((nf+1)/2) * W/nf * 0.18u'"
pd="'2*int((nf+1)/2) * (W/nf + 0.18u)'"
as="'int((nf+2)/2) * W/nf * 0.18u'"
ps="'2*int((nf+2)/2) * (W/nf + 0.18u)'"
nrd="'0.18u / W'" nrs="'0.18u / W'"
sa=0 sb=0 sd=0
model=nfet_06v0
spiceprefix=X
}
C {code_shown.sym} -550 -60 0 0 {name=MODELS only_toplevel=false value=".include /foss/pdks/gf180mcuD/libs.tech/ngspice/design.ngspice
.lib /foss/pdks/gf180mcuD/libs.tech/ngspice/sm141064.ngspice typical
.lib /foss/pdks/gf180mcuD/libs.tech/ngspice/smbb000149.ngspice typical
.lib /foss/pdks/gf180mcuD/libs.tech/ngspice/sm141064.ngspice cap_mim
.lib /foss/pdks/gf180mcuD/libs.tech/ngspice/sm141064.ngspice mimcap_typical"}
C {code_shown.sym} 790 260 0 0 {name=NGSPICE only_toplevel=false value="
*.tran 10p 0.3u
.dc VINP 0.001 5 0.1 
.save all
.control
run
let slope =deriv(v(vout))
meas dc minslope MIN slope
let gain = minslope
print gain
plot gain
plot slope
*plot v(vout) v(vinn) v(vinp)

plot v(vout) vs v(vinp)
plot i(VINP)

let Rin = v(vinn)/ -i(vinn)
#plot Rin vs v(vinp)

.dc VINP 2.5 5 0.1
let Rf = (v(vout) - v(vinp)) / -i(VINP)
#plot Rf vs v(vinp)

.endc"

}
C {vsource.sym} -1710 920 0 0 {name=V2 value=0 savecurrent=false}
C {gnd.sym} -1710 980 0 0 {name=l1 lab=0}
C {lab_pin.sym} -1710 840 0 0 {name=p7 sig_type=std_logic lab=VSS}
C {vsource.sym} -1630 920 0 0 {name=V3 value=5 savecurrent=false}
C {gnd.sym} -1630 980 0 0 {name=l2 lab=0}
C {lab_pin.sym} -1630 840 0 0 {name=p8 sig_type=std_logic lab=VDD}
C {vsource.sym} -1550 920 0 0 {name=VGRF value=2.5 savecurrent=false}
C {gnd.sym} -1550 980 0 0 {name=l3 lab=0}
C {lab_pin.sym} -1550 840 0 0 {name=p10 sig_type=std_logic lab=VRF}
C {vsource.sym} -1390 910 0 0 {name=VINP value=1 savecurrent=false}
C {gnd.sym} -1390 970 0 0 {name=l4 lab=0}
C {lab_pin.sym} -1390 830 0 0 {name=p9 sig_type=std_logic lab=vinp}
C {vsource.sym} -1310 910 0 0 {name=VINN value=2.5 savecurrent=false}
C {gnd.sym} -1310 970 0 0 {name=VINN1 lab=0}
C {lab_pin.sym} -1310 830 0 0 {name=VINN2 sig_type=std_logic lab=vinn}
C {vsource.sym} -1480 920 0 0 {name=VR1 value=2.5 savecurrent=false}
C {gnd.sym} -1480 980 0 0 {name=l5 lab=0}
C {lab_pin.sym} -1480 840 0 0 {name=p22 sig_type=std_logic lab=VR1}
C {symbols/nfet_06v0.sym} -1030 870 0 0 {name=M51
L=1u
W=3.5u
nf=1
m=1
ad="'int((nf+1)/2) * W/nf * 0.18u'"
pd="'2*int((nf+1)/2) * (W/nf + 0.18u)'"
as="'int((nf+2)/2) * W/nf * 0.18u'"
ps="'2*int((nf+2)/2) * (W/nf + 0.18u)'"
nrd="'0.18u / W'" nrs="'0.18u / W'"
sa=0 sb=0 sd=0
model=nfet_06v0
spiceprefix=X
}
C {symbols/nfet_06v0.sym} -770 870 0 0 {name=M52
L=1u
W=8.5u
nf=1
m=1
ad="'int((nf+1)/2) * W/nf * 0.18u'"
pd="'2*int((nf+1)/2) * (W/nf + 0.18u)'"
as="'int((nf+2)/2) * W/nf * 0.18u'"
ps="'2*int((nf+2)/2) * (W/nf + 0.18u)'"
nrd="'0.18u / W'" nrs="'0.18u / W'"
sa=0 sb=0 sd=0
model=nfet_06v0
spiceprefix=X
}
C {lab_pin.sym} -970 910 2 0 {name=p6 sig_type=std_logic lab=VSS}
C {lab_pin.sym} -1120 870 0 0 {name=p11 sig_type=std_logic lab=VR1}
C {symbols/nfet_06v0.sym} -1030 1070 0 0 {name=M53
L=1u
W=3.5u
nf=1
m=1
ad="'int((nf+1)/2) * W/nf * 0.18u'"
pd="'2*int((nf+1)/2) * (W/nf + 0.18u)'"
as="'int((nf+2)/2) * W/nf * 0.18u'"
ps="'2*int((nf+2)/2) * (W/nf + 0.18u)'"
nrd="'0.18u / W'" nrs="'0.18u / W'"
sa=0 sb=0 sd=0
model=nfet_06v0
spiceprefix=X
}
C {lab_pin.sym} -970 1100 2 0 {name=p12 sig_type=std_logic lab=VSS}
C {lab_pin.sym} -1120 1070 0 0 {name=p13 sig_type=std_logic lab=VR1}
C {lab_pin.sym} -700 900 2 0 {name=p14 sig_type=std_logic lab=VSS}
C {lab_pin.sym} -850 870 0 0 {name=p15 sig_type=std_logic lab=VRF}
C {symbols/nfet_06v0.sym} -770 1070 0 0 {name=M54
L=1u
W=8.5u
nf=1
m=1
ad="'int((nf+1)/2) * W/nf * 0.18u'"
pd="'2*int((nf+1)/2) * (W/nf + 0.18u)'"
as="'int((nf+2)/2) * W/nf * 0.18u'"
ps="'2*int((nf+2)/2) * (W/nf + 0.18u)'"
nrd="'0.18u / W'" nrs="'0.18u / W'"
sa=0 sb=0 sd=0
model=nfet_06v0
spiceprefix=X
}
C {lab_pin.sym} -750 1140 0 0 {name=p16 sig_type=std_logic lab=VSS}
C {lab_pin.sym} -850 1070 0 0 {name=p17 sig_type=std_logic lab=VRF}
C {devices/opin.sym} -750 800 0 0 {name=p18 lab=vout}
C {lab_pin.sym} -1010 800 2 0 {name=p19 sig_type=std_logic lab=INN}
C {lab_pin.sym} -280 310 2 0 {name=p20 sig_type=std_logic lab=INN}
C {lab_pin.sym} -950 390 0 0 {name=p21 sig_type=std_logic lab=INP}
C {lab_pin.sym} -1010 1010 0 0 {name=p23 sig_type=std_logic lab=INP}
